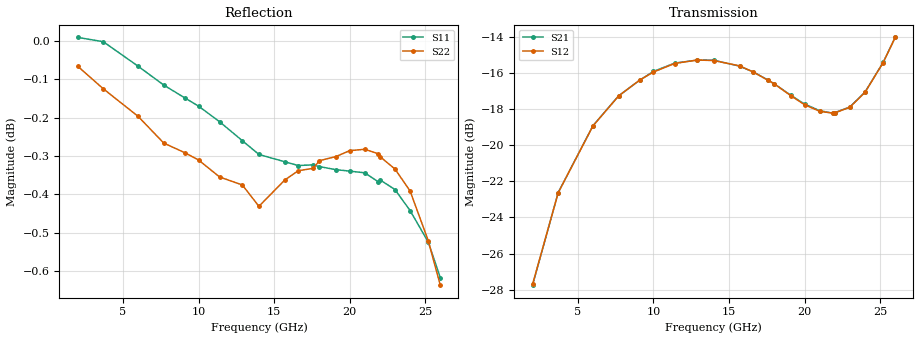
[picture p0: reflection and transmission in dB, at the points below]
! CHUO DENSHI KOGYO Co.,Ltd.
! 1. March 2016
! CKRF7520CK34
! N-channel HJ-FET
! Vds = 0 V Vgs = -2.5 V
# Hz S  MA  R 50
!  f  S11  S21  S12  S22
!  Hz  MAG  ANG  MAG  ANG  MAG  ANG  MAG  ANG
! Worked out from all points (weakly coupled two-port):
!   241 points, 2 GHz to 26 GHz, reference 50 ohm
!   highest |S21| = -14.03 dB at 26 GHz (marker M1); lowest = -27.8 dB at 2 GHz (marker M2)
!   lowest |S11| = -0.6 dB at 26 GHz (marker M3), VSWR 28.18, Z = 55.6 + j270 ohm
!   |S11| at or under -10 dB: nowhere
!   |S22| runs from -0.6 to -0.1 dB; largest |S21 - S12| = 0.0014
!   S11 on the Smith chart (normalised r, x): 2 GHz: -0.02, -5.26; 7.7 GHz: 0.01, -1.11; 12.9 GHz: 0.02, -0.30; 17.6 GHz: 0.02, +0.28; 21.9 GHz: 0.05, +1.09; 26 GHz: 1.11, +5.40
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2e9  1.001 -21.5  0.04097 68.1  0.04114 67.6  0.9924 -21.7
3.7e9  0.9997 -39.8  0.07392 49.5  0.07388 49.5  0.9857 -40.1
6e9  0.9924 -64.9  0.1132 24.5  0.1131 24.6  0.9776 -64.8
7.7e9  0.9868 -84.0  0.137 5.5  0.1369 5.4  0.9698 -83.1
9.1e9  0.983 -99.8  0.1514 -9.8  0.1515 -9.6  0.967 -98.4
1e10  0.9806 -110.6  0.16 -20.1  0.1594 -20.0  0.9649 -108.5
1.14e10  0.976 -127.7  0.1687 -36.4  0.1683 -36.3  0.96 -124.2
1.29e10  0.9705 -146.6  0.172 -54.4  0.1721 -54.4  0.9577 -141.7
1.4e10  0.9665 -161.0  0.1718 -67.5  0.1715 -67.3  0.9516 -154.7
1.57e10  0.9644 175.8  0.1655 -90.3  0.1658 -90.1  0.9591 -175.6
1.66e10  0.9633 163.3  0.1595 -102.3  0.1595 -102.2  0.9618 172.9
1.76e10  0.9635 148.9  0.1513 -116.4  0.1511 -116.3  0.9625 159.8
1.8e10  0.963 143.2  0.1478 -122.1  0.1478 -121.9  0.9647 154.5
1.91e10  0.9621 126.9  0.1374 -138.1  0.137 -137.9  0.9659 139.7
2e10  0.9617 113.5  0.13 -151.3  0.1294 -151.1  0.9676 127.3
2.1e10  0.9612 98.7  0.1246 -166.4  0.1241 -166.2  0.968 113.3
2.19e10  0.9586 85.1  0.1225 179.5  0.1226 179.8  0.9667 100.6
2.2e10  0.9592 83.6  0.123 178.0  0.1228 178.3  0.9659 99.2
2.3e10  0.9564 68.4  0.1276 162.1  0.1274 162.3  0.9623 84.7
2.4e10  0.9504 53.0  0.1402 146.0  0.14 146.2  0.956 69.9
2.52e10  0.9415 33.5  0.1694 126.2  0.1692 126.6  0.9419 51.7
2.6e10  0.9315 20.2  0.1987 112.7  0.1988 113.0  0.9294 38.9
